One B-rep face of a CAD part: STEP entity #363.
In plain terms, the planar face has unit normal (1, 0, 0).
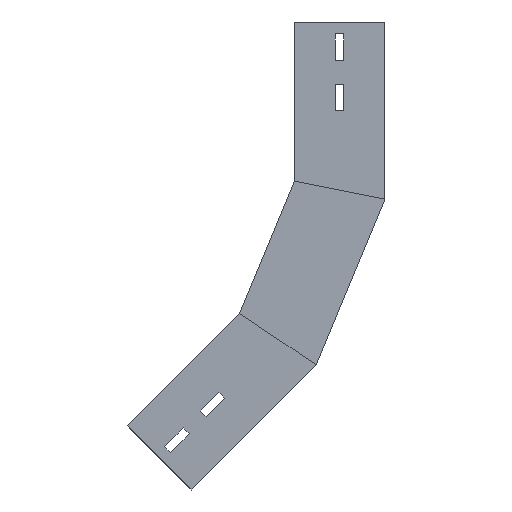
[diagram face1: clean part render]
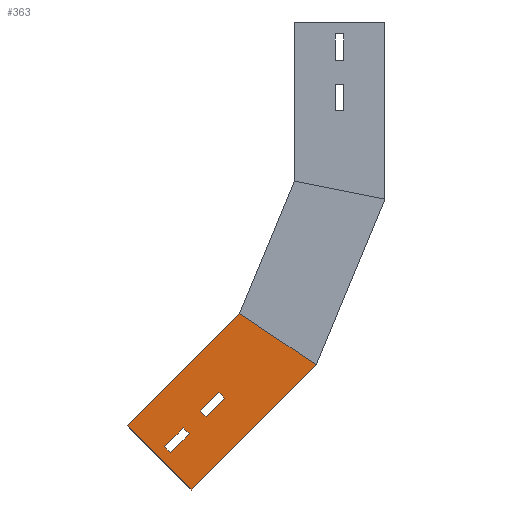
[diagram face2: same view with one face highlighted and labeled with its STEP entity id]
Its self-contained STEP definition (entity closure, numbers rounded to 3 decimals):
#4 = LINE ( 'NONE', #1400, #27 ) ;
#27 = VECTOR ( 'NONE', #1159, 1000. ) ;
#34 = ORIENTED_EDGE ( 'NONE', *, *, #862, .F. ) ;
#38 = FACE_BOUND ( 'NONE', #861, .T. ) ;
#67 = CARTESIAN_POINT ( 'NONE',  ( 0., 0., 0. ) ) ;
#74 = CARTESIAN_POINT ( 'NONE',  ( 0., 34., -73.505 ) ) ;
#80 = ORIENTED_EDGE ( 'NONE', *, *, #451, .T. ) ;
#90 = CARTESIAN_POINT ( 'NONE',  ( 0., 41., -51.505 ) ) ;
#147 = EDGE_LOOP ( 'NONE', ( #34, #361, #522, #923 ) ) ;
#184 = CARTESIAN_POINT ( 'NONE',  ( 0., 34., -51.505 ) ) ;
#190 = DIRECTION ( 'NONE',  ( 0., 0., -1. ) ) ;
#210 = DIRECTION ( 'NONE',  ( 0., 1., 0. ) ) ;
#226 = ORIENTED_EDGE ( 'NONE', *, *, #1062, .T. ) ;
#236 = CARTESIAN_POINT ( 'NONE',  ( 0., 75., -131.682 ) ) ;
#261 = CARTESIAN_POINT ( 'NONE',  ( 0., 0., 0. ) ) ;
#287 = VERTEX_POINT ( 'NONE', #236 ) ;
#299 = FACE_OUTER_BOUND ( 'NONE', #147, .T. ) ;
#314 = AXIS2_PLACEMENT_3D ( 'NONE', #67, #1416, #380 ) ;
#351 = EDGE_CURVE ( 'NONE', #948, #853, #1208, .T. ) ;
#361 = ORIENTED_EDGE ( 'NONE', *, *, #1248, .F. ) ;
#363 = ADVANCED_FACE ( 'NONE', ( #1088, #299, #38 ), #512, .F. ) ;
#367 = VECTOR ( 'NONE', #1462, 1000. ) ;
#380 = DIRECTION ( 'NONE',  ( 0., 0., 1. ) ) ;
#398 = VERTEX_POINT ( 'NONE', #1424 ) ;
#412 = DIRECTION ( 'NONE',  ( 0., 0., -1. ) ) ;
#419 = VECTOR ( 'NONE', #528, 1000. ) ;
#421 = EDGE_CURVE ( 'NONE', #1260, #541, #846, .T. ) ;
#425 = LINE ( 'NONE', #662, #419 ) ;
#428 = CARTESIAN_POINT ( 'NONE',  ( 0., 41., -73.505 ) ) ;
#432 = ORIENTED_EDGE ( 'NONE', *, *, #1198, .T. ) ;
#439 = VECTOR ( 'NONE', #210, 1000. ) ;
#440 = LINE ( 'NONE', #1104, #367 ) ;
#451 = EDGE_CURVE ( 'NONE', #594, #1107, #606, .T. ) ;
#455 = VECTOR ( 'NONE', #1186, 1000. ) ;
#467 = VERTEX_POINT ( 'NONE', #612 ) ;
#509 = CARTESIAN_POINT ( 'NONE',  ( 0., 41., -9.835 ) ) ;
#512 = PLANE ( 'NONE',  #314 ) ;
#515 = LINE ( 'NONE', #261, #439 ) ;
#522 = ORIENTED_EDGE ( 'NONE', *, *, #421, .T. ) ;
#528 = DIRECTION ( 'NONE',  ( 0., -0.981, -0.195 ) ) ;
#541 = VERTEX_POINT ( 'NONE', #1129 ) ;
#545 = DIRECTION ( 'NONE',  ( 0., 1., 0. ) ) ;
#564 = EDGE_CURVE ( 'NONE', #853, #467, #896, .T. ) ;
#578 = EDGE_CURVE ( 'NONE', #1413, #948, #788, .T. ) ;
#581 = CARTESIAN_POINT ( 'NONE',  ( 0., 41., -9.835 ) ) ;
#592 = VECTOR ( 'NONE', #1439, 1000. ) ;
#594 = VERTEX_POINT ( 'NONE', #782 ) ;
#606 = LINE ( 'NONE', #1057, #455 ) ;
#608 = DIRECTION ( 'NONE',  ( 0., -1., 0. ) ) ;
#612 = CARTESIAN_POINT ( 'NONE',  ( 0., 41., -51.505 ) ) ;
#633 = CARTESIAN_POINT ( 'NONE',  ( 0., 0., 0. ) ) ;
#654 = ORIENTED_EDGE ( 'NONE', *, *, #564, .T. ) ;
#662 = CARTESIAN_POINT ( 'NONE',  ( 0., 28.051, -141.02 ) ) ;
#716 = CARTESIAN_POINT ( 'NONE',  ( 0., 41., -31.835 ) ) ;
#722 = VECTOR ( 'NONE', #1126, 1000. ) ;
#751 = VERTEX_POINT ( 'NONE', #1438 ) ;
#779 = ORIENTED_EDGE ( 'NONE', *, *, #351, .T. ) ;
#782 = CARTESIAN_POINT ( 'NONE',  ( 0., 34., -9.835 ) ) ;
#788 = LINE ( 'NONE', #428, #1466 ) ;
#805 = CARTESIAN_POINT ( 'NONE',  ( 0., 41., -73.505 ) ) ;
#846 = LINE ( 'NONE', #858, #907 ) ;
#853 = VERTEX_POINT ( 'NONE', #1355 ) ;
#858 = CARTESIAN_POINT ( 'NONE',  ( 0., 0., 0. ) ) ;
#861 = EDGE_LOOP ( 'NONE', ( #80, #1064, #432, #226 ) ) ;
#862 = EDGE_CURVE ( 'NONE', #994, #287, #440, .T. ) ;
#866 = VECTOR ( 'NONE', #190, 1000. ) ;
#896 = LINE ( 'NONE', #90, #1344 ) ;
#900 = EDGE_CURVE ( 'NONE', #467, #1413, #1477, .T. ) ;
#907 = VECTOR ( 'NONE', #412, 1000. ) ;
#923 = ORIENTED_EDGE ( 'NONE', *, *, #1312, .F. ) ;
#948 = VERTEX_POINT ( 'NONE', #74 ) ;
#986 = DIRECTION ( 'NONE',  ( 0., -1., 0. ) ) ;
#994 = VERTEX_POINT ( 'NONE', #1367 ) ;
#998 = CARTESIAN_POINT ( 'NONE',  ( 0., 41., -51.505 ) ) ;
#1057 = CARTESIAN_POINT ( 'NONE',  ( 0., 41., -9.835 ) ) ;
#1062 = EDGE_CURVE ( 'NONE', #751, #594, #4, .T. ) ;
#1064 = ORIENTED_EDGE ( 'NONE', *, *, #1408, .T. ) ;
#1082 = EDGE_LOOP ( 'NONE', ( #654, #1231, #1235, #779 ) ) ;
#1088 = FACE_BOUND ( 'NONE', #1082, .T. ) ;
#1104 = CARTESIAN_POINT ( 'NONE',  ( 0., 75., 0. ) ) ;
#1107 = VERTEX_POINT ( 'NONE', #509 ) ;
#1109 = LINE ( 'NONE', #581, #722 ) ;
#1126 = DIRECTION ( 'NONE',  ( 0., 0., -1. ) ) ;
#1129 = CARTESIAN_POINT ( 'NONE',  ( 0., 0., -146.6 ) ) ;
#1159 = DIRECTION ( 'NONE',  ( 0., 0., 1. ) ) ;
#1186 = DIRECTION ( 'NONE',  ( 0., 1., 0. ) ) ;
#1188 = LINE ( 'NONE', #716, #1250 ) ;
#1198 = EDGE_CURVE ( 'NONE', #398, #751, #1188, .T. ) ;
#1208 = LINE ( 'NONE', #184, #592 ) ;
#1231 = ORIENTED_EDGE ( 'NONE', *, *, #900, .T. ) ;
#1235 = ORIENTED_EDGE ( 'NONE', *, *, #578, .T. ) ;
#1248 = EDGE_CURVE ( 'NONE', #1260, #994, #515, .T. ) ;
#1250 = VECTOR ( 'NONE', #608, 1000. ) ;
#1260 = VERTEX_POINT ( 'NONE', #633 ) ;
#1312 = EDGE_CURVE ( 'NONE', #287, #541, #425, .T. ) ;
#1344 = VECTOR ( 'NONE', #545, 1000. ) ;
#1355 = CARTESIAN_POINT ( 'NONE',  ( 0., 34., -51.505 ) ) ;
#1367 = CARTESIAN_POINT ( 'NONE',  ( 0., 75., 0. ) ) ;
#1400 = CARTESIAN_POINT ( 'NONE',  ( 0., 34., -9.835 ) ) ;
#1408 = EDGE_CURVE ( 'NONE', #1107, #398, #1109, .T. ) ;
#1413 = VERTEX_POINT ( 'NONE', #805 ) ;
#1416 = DIRECTION ( 'NONE',  ( -1., 0., 0. ) ) ;
#1424 = CARTESIAN_POINT ( 'NONE',  ( 0., 41., -31.835 ) ) ;
#1438 = CARTESIAN_POINT ( 'NONE',  ( 0., 34., -31.835 ) ) ;
#1439 = DIRECTION ( 'NONE',  ( 0., 0., 1. ) ) ;
#1462 = DIRECTION ( 'NONE',  ( 0., 0., -1. ) ) ;
#1466 = VECTOR ( 'NONE', #986, 1000. ) ;
#1477 = LINE ( 'NONE', #998, #866 ) ;
